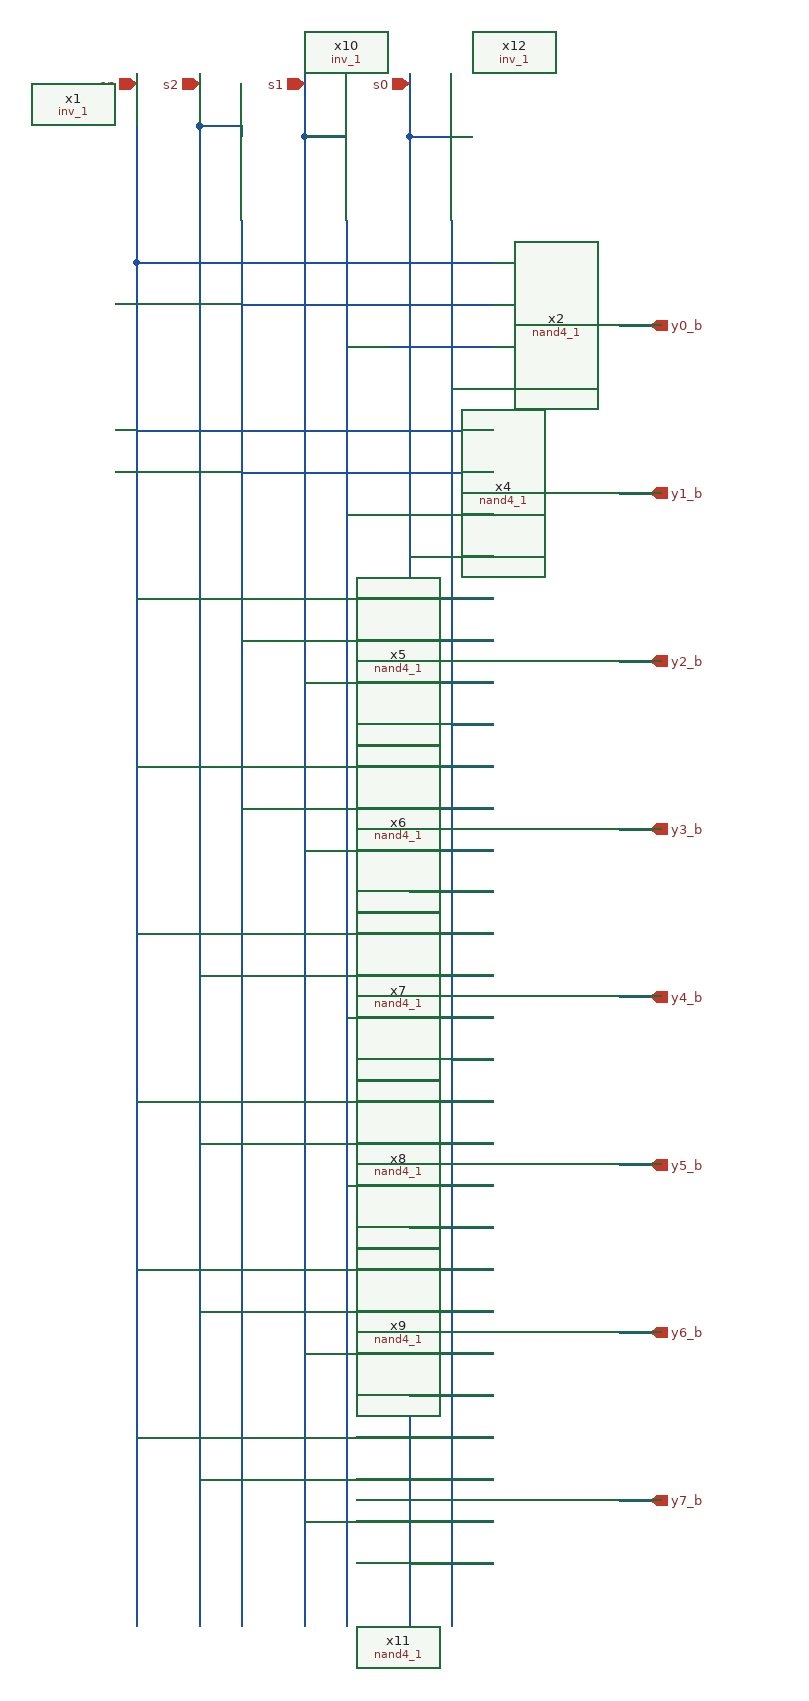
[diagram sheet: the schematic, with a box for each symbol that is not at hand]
v {xschem version=3.0.0 file_version=1.2 }
G {}
K {}
V {}
S {}
E {}
N -1289200 -414400 -1289200 -414360 { lab=s1}
N -1289100 -414400 -1289100 -414360 { lab=s0}
N -1289280 -414240 -1289020 -414240 { lab=en}
N -1288900 -414180 -1288860 -414180 { lab=y0_b}
N -1288900 -414020 -1288860 -414020 { lab=y1_b}
N -1288900 -413860 -1288860 -413860 { lab=y2_b}
N -1288900 -413700 -1288860 -413700 { lab=y3_b}
N -1288900 -413540 -1288860 -413540 { lab=y4_b}
N -1288900 -413380 -1288860 -413380 { lab=y5_b}
N -1288900 -413220 -1288860 -413220 { lab=y6_b}
N -1288900 -413060 -1288860 -413060 { lab=y7_b}
N -1289360 -414240 -1289280 -414240 { lab=en}
N -1289360 -414240 -1289360 -413480 { lab=en}
N -1289360 -413480 -1289360 -412940 { lab=en}
N -1289360 -414080 -1289020 -414080 { lab=en}
N -1289360 -413920 -1289020 -413920 { lab=en}
N -1289360 -413760 -1289020 -413760 { lab=en}
N -1289360 -413600 -1289020 -413600 { lab=en}
N -1289360 -413440 -1289020 -413440 { lab=en}
N -1289360 -413280 -1289020 -413280 { lab=en}
N -1289360 -413120 -1289020 -413120 { lab=en}
N -1289200 -414360 -1289160 -414360 { lab=s1}
N -1289100 -414360 -1289060 -414360 { lab=s0}
N -1289300 -414360 -1289300 -412940 { lab=s2}
N -1289260 -414280 -1289260 -412940 { lab=#net1}
N -1289200 -414360 -1289200 -412940 { lab=s1}
N -1289160 -414280 -1289160 -412940 { lab=#net2}
N -1289100 -414360 -1289100 -412940 { lab=s0}
N -1289060 -414280 -1289060 -412940 { lab=#net3}
N -1289260 -414200 -1289020 -414200 { lab=#net1}
N -1289160 -414160 -1289020 -414160 { lab=#net2}
N -1289060 -414120 -1289020 -414120 { lab=#net3}
N -1289260 -414040 -1289020 -414040 { lab=#net1}
N -1289160 -414000 -1289020 -414000 { lab=#net2}
N -1289100 -413960 -1289020 -413960 { lab=s0}
N -1289260 -413880 -1289020 -413880 { lab=#net1}
N -1289200 -413840 -1289020 -413840 { lab=s1}
N -1289060 -413800 -1289020 -413800 { lab=#net3}
N -1289260 -413720 -1289020 -413720 { lab=#net1}
N -1289200 -413680 -1289020 -413680 { lab=s1}
N -1289100 -413640 -1289020 -413640 { lab=s0}
N -1289300 -413560 -1289020 -413560 { lab=s2}
N -1289160 -413520 -1289020 -413520 { lab=#net2}
N -1289060 -413480 -1289020 -413480 { lab=#net3}
N -1289300 -413400 -1289020 -413400 { lab=s2}
N -1289160 -413360 -1289020 -413360 { lab=#net2}
N -1289100 -413320 -1289020 -413320 { lab=s0}
N -1289300 -413240 -1289020 -413240 { lab=s2}
N -1289200 -413200 -1289020 -413200 { lab=s1}
N -1289100 -413160 -1289020 -413160 { lab=s0}
N -1289300 -413080 -1289020 -413080 { lab=s2}
N -1289200 -413040 -1289020 -413040 { lab=s1}
N -1289100 -413000 -1289020 -413000 { lab=s0}
N -1289360 -414390 -1289360 -414240 { lab=en}
N -1289300 -414370 -1289300 -414360 { lab=s2}
N -1289260 -414370 -1289260 -414360 { lab=s2}
N -1289300 -414370 -1289260 -414370 { lab=s2}
N -1289200 -414420 -1289200 -414400 { lab=s1}
N -1289100 -414420 -1289100 -414400 { lab=s0}
N -1289300 -414420 -1289300 -414370 { lab=s2}
N -1289360 -414420 -1289360 -414390 { lab=en}
C {devices/ipin.sym} -1289360 -414410 1 0 {name=p1 lab=en
}
C {devices/ipin.sym} -1289300 -414410 1 0 {name=p4 lab=s2
}
C {devices/ipin.sym} -1289100 -414410 1 0 {name=p6 lab=s0

}
C {devices/opin.sym} -1288870 -414180 0 0 {name=p2 lab=y0_b

}
C {devices/opin.sym} -1288870 -414020 0 0 {name=p3 lab=y1_b
}
C {devices/opin.sym} -1288870 -413860 0 0 {name=p7 lab=y2_b


}
C {devices/opin.sym} -1288870 -413700 0 0 {name=p8 lab=y3_b


}
C {devices/opin.sym} -1288870 -413540 0 0 {name=p9 lab=y4_b


}
C {devices/opin.sym} -1288870 -413380 0 0 {name=p10 lab=y5_b


}
C {devices/opin.sym} -1288870 -413220 0 0 {name=p11 lab=y6_b



}
C {devices/opin.sym} -1288870 -413060 0 0 {name=p12 lab=y7_b



}
C {devices/ipin.sym} -1289200 -414410 1 0 {name=p5 lab=s1
}
C {sky130_stdcells/nand4_1.sym} -1288960 -414020 0 0 {name=x4 VGND=VGND VNB=VNB VPB=VPB VPWR=VPWR prefix=sky130_fd_sc_hd__ }
C {sky130_stdcells/nand4_1.sym} -1288960 -413860 0 0 {name=x5 VGND=VGND VNB=VNB VPB=VPB VPWR=VPWR prefix=sky130_fd_sc_hd__ }
C {sky130_stdcells/nand4_1.sym} -1288960 -413700 0 0 {name=x6 VGND=VGND VNB=VNB VPB=VPB VPWR=VPWR prefix=sky130_fd_sc_hd__ }
C {sky130_stdcells/nand4_1.sym} -1288960 -413540 0 0 {name=x7 VGND=VGND VNB=VNB VPB=VPB VPWR=VPWR prefix=sky130_fd_sc_hd__ }
C {sky130_stdcells/nand4_1.sym} -1288960 -413380 0 0 {name=x8 VGND=VGND VNB=VNB VPB=VPB VPWR=VPWR prefix=sky130_fd_sc_hd__ }
C {sky130_stdcells/nand4_1.sym} -1288960 -413220 0 0 {name=x9 VGND=VGND VNB=VNB VPB=VPB VPWR=VPWR prefix=sky130_fd_sc_hd__ }
C {sky130_stdcells/nand4_1.sym} -1288960 -413060 0 0 {name=x11 VGND=VGND VNB=VNB VPB=VPB VPWR=VPWR prefix=sky130_fd_sc_hd__ }
C {sky130_stdcells/inv_1.sym} -1289260 -414320 1 0 {name=x1 VGND=VGND VNB=VNB VPB=VPB VPWR=VPWR prefix=sky130_fd_sc_hd__ }
C {sky130_stdcells/nand4_1.sym} -1288960 -414180 0 0 {name=x2 VGND=VGND VNB=VNB VPB=VPB VPWR=VPWR prefix=sky130_fd_sc_hd__ }
C {sky130_stdcells/inv_1.sym} -1289160 -414320 1 0 {name=x10 VGND=VGND VNB=VNB VPB=VPB VPWR=VPWR prefix=sky130_fd_sc_hd__ }
C {sky130_stdcells/inv_1.sym} -1289060 -414320 1 0 {name=x12 VGND=VGND VNB=VNB VPB=VPB VPWR=VPWR prefix=sky130_fd_sc_hd__ }
